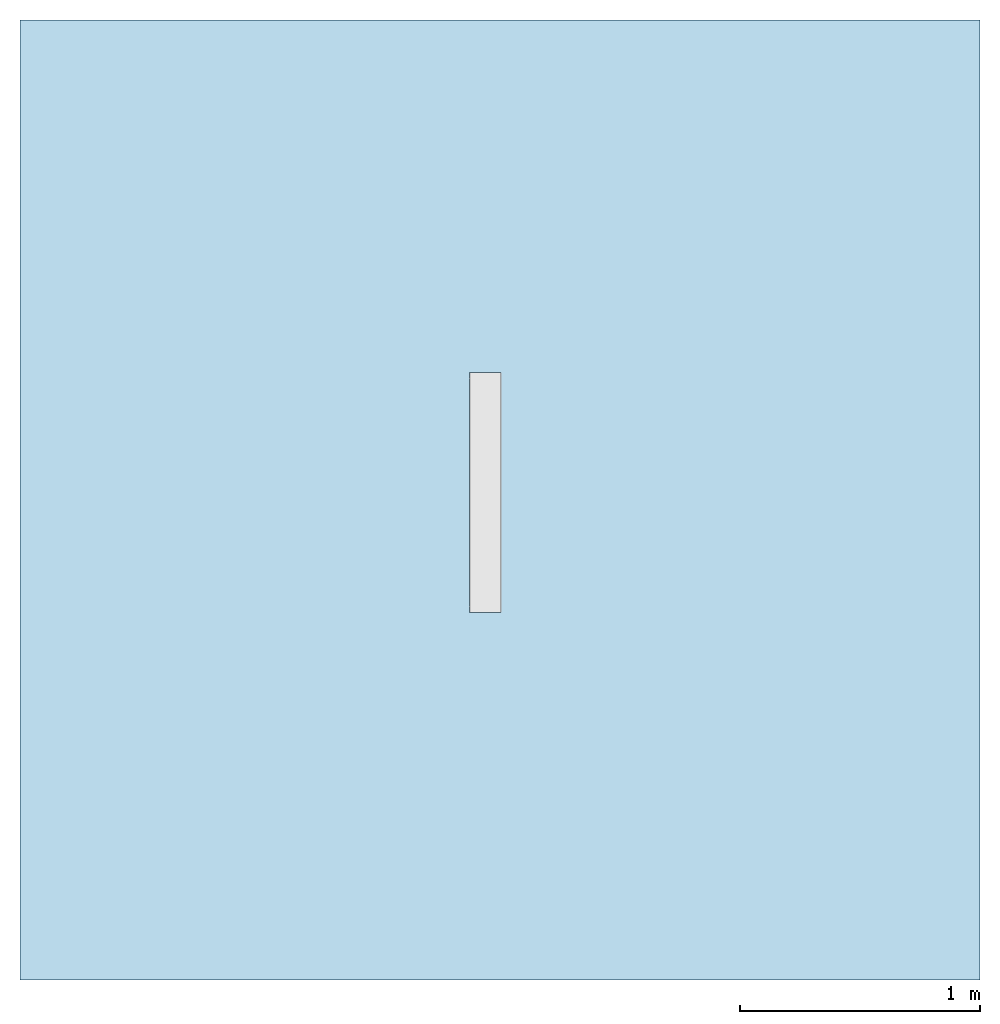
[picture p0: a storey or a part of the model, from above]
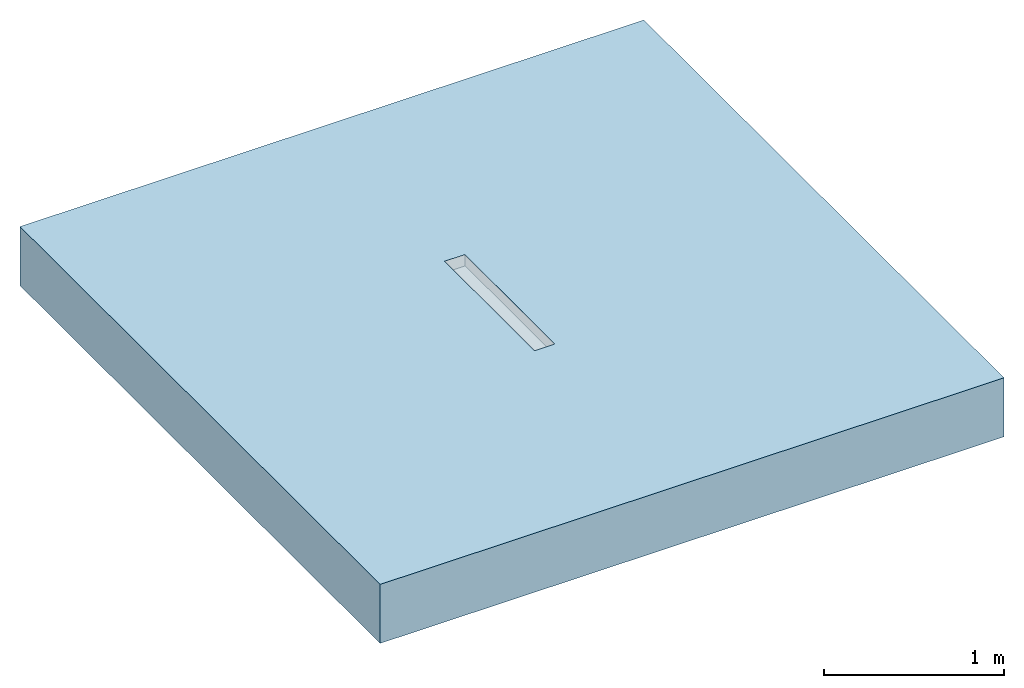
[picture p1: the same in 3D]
Properties of the parts of a building model (IFC2X3)

# File
Description: ViewDefinition [CoordinationView]
File name: Project Number
Time: 2014-06-06T14:32:00
Written by: The EXPRESS Data Manager Version 5.01.0100.02.64mod : 6 Jun 2012
Made in: 20130308_1515(x64) - Exporter 2014.0.2013.0308 - Default UI
Comment: STEP Physical File produced by: The EXPRESS Data Manager Version 5.01.0100.02.64mod : 6 Jun 2012 * Module: EDMstepFileFactory/EDMstandAlone * Creation date: Fri Jun 06 14:32:00 2014 * Host: IN-BLR-PC-0010 * Database: C:\Users\palleri\AppData\Local\Temp\{FAA3AF48-6633-4AA7-BDC6-40FA6D4DCAB0}\ifc * Database version: 5507 * Database creation date: Fri Jun 06 14:31:57 2014 * Schema: IFC2X3 * Model: DataRepository.ifc * Model creation date: Fri Jun 06 14:31:57 2014 * Header model: DataRepository.ifc_HeaderModel * Header model creation date: Fri Jun 06 14:31:57 2014 * EDMuser: sdai-user * EDMgroup: sdai-group * License ID and type: 5605 : Permanent license. Expiry date: * EDMstepFileFactory options: 020000

# IfcProject, Project Number
LongName: Project Name; Phase: Project Status

# IfcSite, Default
RefLatitude: 42, 21, 30, 344238; RefLongitude: -71, -3, -35, -194702; RefElevation: 0 mm

# IfcBuilding
Pset_BuildingCommon - NumberOfStoreys: 1
Other - Project Address: ## Street City, State Zip; Project Number: Project Number; Client Name: Owner; Project Status: Project Status; Project Issue Date: Issue Date; Project Name: Project Name

# IfcBuildingStorey, Level 1
LongName: Level 1; Elevation: 0 mm
Constraints - Elevation Base: Project Base Point; Elevation: 0 mm
Graphics - Line Weight: 1; Color: 0; Symbol at End 1 Default: no; Symbol: M_Level Head - Circle: M_Level Head - Circle; Line Pattern: Center; Symbol at End 2 Default: yes
Identity Data - Building Story: yes; Name: Level 1; Structural: no
Dimensions - Computation Height: 0 mm

# IfcFlowTerminal: 36941 - Adjustable Channel - Shallow Section - 1000mm LG - Invert Depth 55/77mm, ACO Freedeck Adjustable Height Channel Shallow Section Galvanized Steel:36941 - Adjustable Channel - Shallow Section - 1000mm LG - Invert Depth 55/77mm:309629
In: Level 1
Material: Galvanized Steel
Dimensions - Height @ Invert 1 (55 -77mm): 77 mm; Height @ Invert 2 (55 -77mm): 77 mm; Channel End Length: -1000 mm; Grating End Length: 1000 mm
Other - Height @ Invert 2 Min & Max: 77 mm; Top Piece Void Height @ Invert 1: 31 mm; Top Piece Void Height @ Invert 2: 31 mm; Height @ Invert 1 Min & Max: 77 mm; Nos: 32
Construction - 36952 - Grating - Plain Mesh - Galvanised Steel - 500mm long: no; 00277 - Grating - Slotted Grating - Galvanised Steel - 500mm long: no; 00276 - Grating - Slotted Grating - Galvanised Steel - 1000mm long: no; 36953 - Grating - Plain Mesh - Galvanised Steel - 1000mm long: yes; End Plate Invert 1: no; End Plate Invert 2: no
Identity Data - Mark: 28; Manufacturer: ACO Building Drainage; Website: www.acobd.com; Telephone: +44 (0)1462 816666; E-mail Technical: abdtechnical@aco.co.uk; Watermark2: This file is water marked and users are prohibited to reproduce, adapt, distribute this information; Fax: +44 (0)1462 851490; Watermarked By: www.acobd.com; Address: ACO Business Centre, Caxton Road, Bedford, MK41 0LF; Watermarked With: BIM Manager Premium Suite; E-mail Sales: abdcommercial@aco.co.uk; Watermark1: This file is the property of ACO Technologies PLC
Phasing - Phase Created: New Construction
Constraints - Moves With Nearby Elements: no; Level: Level: Level 1
Pset_ManufacturerTypeInformation - Manufacturer: ACO Building Drainage
Model Properties - Grating Product Code 36953: Load Class A15 - Mesh Grating - 14mm x 30mm Mesh - Galvanized Steel - 1000mm long - 3.0kg; Grating Product Code 36952: Load Class A15 - Mesh Grating - 14mm x 30mm Mesh - Galvanized Steel - 500mm long - 1.6kg; Grating Product Code 00277: Load Class A15 - Slotted Grating - 10 x 80mm Slot - Galvanized Steel - 500mm long - 1.0kg; Grating Product Code 00276: Load Class A15 - Slotted Grating - 10 x 80mm Slot - Galvanized Steel - 1000mm long - 2.2kg; End Plate Product Code 36950: End Plate - Galvanized Steel for Invert Depth - 55/77mm - 0.1Kg
General - Channel Colour: Galvanised; Load Class: A15; Product Standard: BS EN 1433:2002, CE marked; Channel Recyclable: Fully recyclable; Channel Material: Hot Dipped Galvanised Steel; Weight (Kg): 4.9kg; Maintenance Guidelines: X:\Electronic Literature\ABD Electronic Literature\Roof and Balcony Drainage\ACO Freedeck Brochure.pdf; Product Type: Linear Deck Drainage System; Product Code: 36941; Installation Guidelines: X:\Electronic Literature\ABD Electronic Literature\Roof and Balcony Drainage\ACO Freedeck Brochure.pdf; Channel Recycled Material Content: 25 - 30 %; Product Description: ACO Freedeck Adjustable Channel - Shallow Section; Price: POA - contact ACO; NBS Specification: NBS Section R10 Gravity Rainwater Drainage Systems, Subsection 365; Dimensions (LxWxH): 1000 x 130 x 55/77; Product Range: ACO Freedeck
Materials and Finishes - Material: Galvanized Steel

# IfcOpeningElement: Recess
In: Level 1
Constraints - Height Offset From Level: 0 mm; Level: Level: Level 1; Related to Mass: no; Room Bounding: yes
Structural - Enable Analytical Model: no; Structural: no
Dimensions - Volume: 6.38981 m3; Area: 16 m2; Perimeter: 16000 mm; Thickness: 400 mm
Phasing - Phase Created: New Construction
Analytical Properties - Absorptance: 0.1; Thermal mass: 604440; Thermal Resistance (R): 0.382409; Heat Transfer Coefficient (U): 2.615; Roughness: 1
Construction - Function: Interior; Default Thickness: 400 mm
Graphics - Coarse Scale Fill Color: 0
Materials and Finishes - Structural Material: Concrete, Broom Finish

# IfcSlab: Floor:Generic Floor - 400mm, Floor:Generic Floor - 400mm:193825
In: Level 1
PredefinedType: FLOOR; Material: Concrete, Broom Finish 400 mm
Constraints - Height Offset From Level: 0 mm; Level: Level: Level 1; Related to Mass: no; Room Bounding: yes
Structural - Enable Analytical Model: no; Structural: no
Dimensions - Volume: 6.38981 m3; Area: 16 m2; Perimeter: 16000 mm; Thickness: 400 mm
Phasing - Phase Created: New Construction
Pset_SlabCommon - Reference: Generic Floor - 400mm; IsExternal: no; LoadBearing: yes; ThermalTransmittance: 2.615 kg/K/s3
Analytical Properties - Absorptance: 0.1; Thermal mass: 604440; Thermal Resistance (R): 0.382409; Heat Transfer Coefficient (U): 2.615; Roughness: 1
Construction - Function: Interior; Default Thickness: 400 mm
Graphics - Coarse Scale Fill Color: 0
Materials and Finishes - Structural Material: Concrete, Broom Finish
